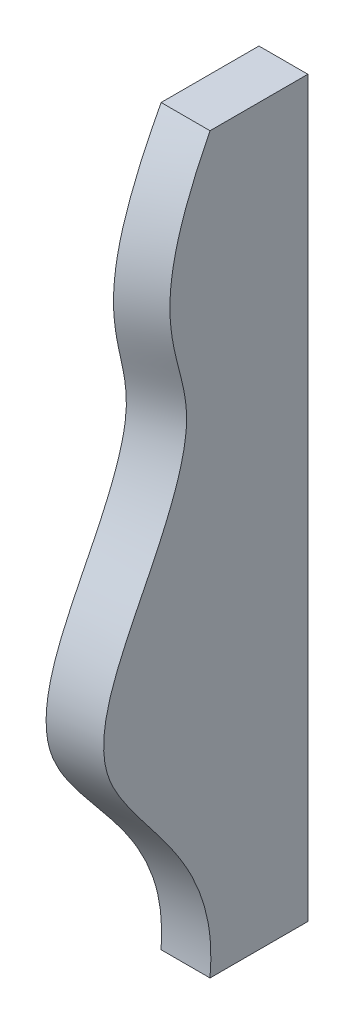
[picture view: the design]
ISO-10303-21;
HEADER;
FILE_DESCRIPTION(('STEP AP214'),'2;1');
FILE_NAME('part.step','',(''),(''),'','','');
FILE_SCHEMA(('AUTOMOTIVE_DESIGN { 1 0 10303 214 1 1 1 1 }'));
ENDSEC;
DATA;
#1=APPLICATION_CONTEXT('core data for automotive mechanical design processes');
#2=APPLICATION_PROTOCOL_DEFINITION('international standard','automotive_design',2000,#1);
#3=PRODUCT_CONTEXT('',#1,'mechanical');
#4=PRODUCT('Part','Part','',(#3));
#5=PRODUCT_RELATED_PRODUCT_CATEGORY('part','',(#4));
#6=PRODUCT_DEFINITION_FORMATION('','',#4);
#7=PRODUCT_DEFINITION_CONTEXT('part definition',#1,'design');
#8=PRODUCT_DEFINITION('design','',#6,#7);
#9=PRODUCT_DEFINITION_SHAPE('','',#8);
#10=(LENGTH_UNIT() NAMED_UNIT(*) SI_UNIT(.MILLI.,.METRE.));
#11=(NAMED_UNIT(*) PLANE_ANGLE_UNIT() SI_UNIT($,.RADIAN.));
#12=(NAMED_UNIT(*) SI_UNIT($,.STERADIAN.) SOLID_ANGLE_UNIT());
#13=UNCERTAINTY_MEASURE_WITH_UNIT(LENGTH_MEASURE(1.E-05),#10,'distance_accuracy_value','');
#14=(GEOMETRIC_REPRESENTATION_CONTEXT(3) GLOBAL_UNCERTAINTY_ASSIGNED_CONTEXT((#13)) GLOBAL_UNIT_ASSIGNED_CONTEXT((#10,
#11,#12)) REPRESENTATION_CONTEXT('',''));
#15=CARTESIAN_POINT('',(0.,0.,0.));
#16=DIRECTION('',(0.,0.,1.));
#17=DIRECTION('',(1.,0.,0.));
#18=AXIS2_PLACEMENT_3D('',#15,#16,#17);
#19=CARTESIAN_POINT('',(250.,375.,253.120113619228));
#20=DIRECTION('',(1.,0.,0.));
#21=DIRECTION('',(0.,0.,-1.));
#22=AXIS2_PLACEMENT_3D('',#19,#20,#21);
#23=PLANE('',#22);
#24=CARTESIAN_POINT('',(250.,375.,100.));
#25=CARTESIAN_POINT('',(250.,373.220474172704,100.903911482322));
#26=CARTESIAN_POINT('',(250.,371.437127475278,101.800322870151));
#27=CARTESIAN_POINT('',(250.,367.861516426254,103.577630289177));
#28=CARTESIAN_POINT('',(250.,366.0692477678,104.458517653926));
#29=CARTESIAN_POINT('',(250.,362.475751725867,106.203616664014));
#30=CARTESIAN_POINT('',(250.,360.674521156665,107.06782175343));
#31=CARTESIAN_POINT('',(250.,357.063025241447,108.778305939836));
#32=CARTESIAN_POINT('',(250.,355.252757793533,109.624580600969));
#33=CARTESIAN_POINT('',(250.,351.623076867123,111.297884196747));
#34=CARTESIAN_POINT('',(250.,349.803662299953,112.12491077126));
#35=CARTESIAN_POINT('',(250.,346.155536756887,113.758313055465));
#36=CARTESIAN_POINT('',(250.,344.326825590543,114.564688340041));
#37=CARTESIAN_POINT('',(250.,340.593071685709,116.184285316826));
#38=CARTESIAN_POINT('',(250.,338.687673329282,116.996687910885));
#39=CARTESIAN_POINT('',(250.,334.866369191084,118.595935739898));
#40=CARTESIAN_POINT('',(250.,332.950464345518,119.382783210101));
#41=CARTESIAN_POINT('',(250.,329.107807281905,120.929005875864));
#42=CARTESIAN_POINT('',(250.,327.181056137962,121.688383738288));
#43=CARTESIAN_POINT('',(250.,323.316308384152,123.177600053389));
#44=CARTESIAN_POINT('',(250.,321.378312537,123.907440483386));
#45=CARTESIAN_POINT('',(250.,317.490611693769,125.335345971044));
#46=CARTESIAN_POINT('',(250.,315.540906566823,126.033410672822));
#47=CARTESIAN_POINT('',(250.,311.629251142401,127.395341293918));
#48=CARTESIAN_POINT('',(250.,309.667299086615,128.059202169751));
#49=CARTESIAN_POINT('',(250.,305.721169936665,129.353164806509));
#50=CARTESIAN_POINT('',(250.,303.736930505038,129.983076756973));
#51=CARTESIAN_POINT('',(250.,299.75582656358,131.202490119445));
#52=CARTESIAN_POINT('',(250.,297.758960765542,131.791987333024));
#53=CARTESIAN_POINT('',(250.,293.752808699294,132.927203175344));
#54=CARTESIAN_POINT('',(250.,291.743522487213,133.47292200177));
#55=CARTESIAN_POINT('',(250.,287.71268752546,134.517031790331));
#56=CARTESIAN_POINT('',(250.,285.691138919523,135.015423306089));
#57=CARTESIAN_POINT('',(250.,281.635891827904,135.961150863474));
#58=CARTESIAN_POINT('',(250.,279.602192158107,136.408481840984));
#59=CARTESIAN_POINT('',(250.,275.522710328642,137.248195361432));
#60=CARTESIAN_POINT('',(250.,273.476924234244,137.6405588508));
#61=CARTESIAN_POINT('',(250.,269.416504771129,138.358665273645));
#62=CARTESIAN_POINT('',(250.,267.40208275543,138.685599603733));
#63=CARTESIAN_POINT('',(250.,263.363817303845,139.278764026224));
#64=CARTESIAN_POINT('',(250.,261.339971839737,139.544980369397));
#65=CARTESIAN_POINT('',(250.,257.285051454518,140.012783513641));
#66=CARTESIAN_POINT('',(250.,255.253977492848,140.214378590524));
#67=CARTESIAN_POINT('',(250.,251.186828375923,140.549420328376));
#68=CARTESIAN_POINT('',(250.,249.150755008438,140.682888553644));
#69=CARTESIAN_POINT('',(250.,245.075897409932,140.878750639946));
#70=CARTESIAN_POINT('',(250.,243.037114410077,140.941169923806));
#71=CARTESIAN_POINT('',(250.,238.959181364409,140.992821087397));
#72=CARTESIAN_POINT('',(250.,236.92003159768,140.982074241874));
#73=CARTESIAN_POINT('',(250.,233.10922731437,140.892630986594));
#74=CARTESIAN_POINT('',(250.,231.337355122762,140.822975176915));
#75=CARTESIAN_POINT('',(250.,227.796421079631,140.627732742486));
#76=CARTESIAN_POINT('',(250.,226.027359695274,140.502137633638));
#77=CARTESIAN_POINT('',(250.,222.493734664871,140.196136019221));
#78=CARTESIAN_POINT('',(250.,220.729171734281,140.015721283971));
#79=CARTESIAN_POINT('',(250.,217.206088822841,139.602317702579));
#80=CARTESIAN_POINT('',(250.,215.447569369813,139.369324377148));
#81=CARTESIAN_POINT('',(250.,211.937980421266,138.85423527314));
#82=CARTESIAN_POINT('',(250.,210.186910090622,138.572145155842));
#83=CARTESIAN_POINT('',(250.,206.693470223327,137.963660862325));
#84=CARTESIAN_POINT('',(250.,204.951096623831,137.637289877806));
#85=CARTESIAN_POINT('',(250.,201.447659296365,136.940741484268));
#86=CARTESIAN_POINT('',(250.,199.686713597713,136.569974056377));
#87=CARTESIAN_POINT('',(250.,196.172554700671,135.796172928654));
#88=CARTESIAN_POINT('',(250.,194.419339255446,135.393149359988));
#89=CARTESIAN_POINT('',(250.,190.918463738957,134.563170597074));
#90=CARTESIAN_POINT('',(250.,189.170804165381,134.136213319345));
#91=CARTESIAN_POINT('',(250.,185.678601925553,133.267747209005));
#92=CARTESIAN_POINT('',(250.,183.934060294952,132.826234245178));
#93=CARTESIAN_POINT('',(250.,180.445427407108,131.938950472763));
#94=CARTESIAN_POINT('',(250.,178.701336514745,131.493178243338));
#95=CARTESIAN_POINT('',(250.,175.210752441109,130.608385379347));
#96=CARTESIAN_POINT('',(250.,173.464258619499,130.169367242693));
#97=CARTESIAN_POINT('',(250.,170.339071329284,129.401270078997));
#98=CARTESIAN_POINT('',(250.,168.961244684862,129.068686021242));
#99=CARTESIAN_POINT('',(250.,166.20164596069,128.420662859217));
#100=CARTESIAN_POINT('',(250.,164.819874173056,128.105222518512));
#101=CARTESIAN_POINT('',(250.,162.051733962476,127.497244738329));
#102=CARTESIAN_POINT('',(250.,160.665367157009,127.204699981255));
#103=CARTESIAN_POINT('',(250.,157.887431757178,126.648053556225));
#104=CARTESIAN_POINT('',(250.,156.495865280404,126.38394139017));
#105=CARTESIAN_POINT('',(250.,153.706996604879,125.889358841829));
#106=CARTESIAN_POINT('',(250.,152.309695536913,125.658882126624));
#107=CARTESIAN_POINT('',(250.,149.508914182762,125.236321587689));
#108=CARTESIAN_POINT('',(250.,148.105432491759,125.044247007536));
#109=CARTESIAN_POINT('',(250.,145.312512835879,124.705202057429));
#110=CARTESIAN_POINT('',(250.,143.923146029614,124.55764958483));
#111=CARTESIAN_POINT('',(250.,141.139536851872,124.307536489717));
#112=CARTESIAN_POINT('',(250.,139.745292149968,124.205001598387));
#113=CARTESIAN_POINT('',(250.,136.95390733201,124.047744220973));
#114=CARTESIAN_POINT('',(250.,135.556766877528,123.993027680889));
#115=CARTESIAN_POINT('',(250.,132.761607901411,123.933312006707));
#116=CARTESIAN_POINT('',(250.,131.363589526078,123.928306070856));
#117=CARTESIAN_POINT('',(250.,128.568653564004,123.969032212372));
#118=CARTESIAN_POINT('',(250.,127.171735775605,124.014749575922));
#119=CARTESIAN_POINT('',(250.,125.078670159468,124.121503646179));
#120=CARTESIAN_POINT('',(250.,124.381497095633,124.163439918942));
#121=CARTESIAN_POINT('',(250.,122.988014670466,124.259976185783));
#122=CARTESIAN_POINT('',(250.,122.291705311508,124.314576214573));
#123=CARTESIAN_POINT('',(250.,121.14390715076,124.415057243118));
#124=CARTESIAN_POINT('',(250.,120.692095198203,124.457293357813));
#125=CARTESIAN_POINT('',(250.,119.788986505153,124.546961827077));
#126=CARTESIAN_POINT('',(250.,119.337689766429,124.594394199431));
#127=CARTESIAN_POINT('',(250.,117.984614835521,124.74416466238));
#128=CARTESIAN_POINT('',(250.,117.083655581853,124.853975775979));
#129=CARTESIAN_POINT('',(250.,115.283863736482,125.092111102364));
#130=CARTESIAN_POINT('',(250.,114.385032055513,125.220442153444));
#131=CARTESIAN_POINT('',(250.,112.590006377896,125.494270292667));
#132=CARTESIAN_POINT('',(250.,111.693812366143,125.639767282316));
#133=CARTESIAN_POINT('',(250.,109.007753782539,126.10046963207));
#134=CARTESIAN_POINT('',(250.,107.221970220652,126.439676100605));
#135=CARTESIAN_POINT('',(250.,103.660474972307,127.17408997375));
#136=CARTESIAN_POINT('',(250.,101.884773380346,127.569345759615));
#137=CARTESIAN_POINT('',(250.,98.3442194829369,128.409090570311));
#138=CARTESIAN_POINT('',(250.,96.5793724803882,128.85360190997));
#139=CARTESIAN_POINT('',(250.,93.9410074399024,129.552917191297));
#140=CARTESIAN_POINT('',(250.,93.0631243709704,129.791421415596));
#141=CARTESIAN_POINT('',(250.,91.3102085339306,130.278689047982));
#142=CARTESIAN_POINT('',(250.,90.4351757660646,130.527452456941));
#143=CARTESIAN_POINT('',(250.,87.7843646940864,131.297049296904));
#144=CARTESIAN_POINT('',(250.,86.0130079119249,131.833170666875));
#145=CARTESIAN_POINT('',(250.,82.4833365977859,132.941367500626));
#146=CARTESIAN_POINT('',(250.,80.7250119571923,133.513410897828));
#147=CARTESIAN_POINT('',(250.,77.220409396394,134.690089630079));
#148=CARTESIAN_POINT('',(250.,75.4741253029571,135.29470660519));
#149=CARTESIAN_POINT('',(250.,71.9927547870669,136.533485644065));
#150=CARTESIAN_POINT('',(250.,70.2576647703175,137.167637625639));
#151=CARTESIAN_POINT('',(250.,66.797916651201,138.462705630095));
#152=CARTESIAN_POINT('',(250.,65.0732565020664,139.123616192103));
#153=CARTESIAN_POINT('',(250.,61.6336938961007,140.469640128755));
#154=CARTESIAN_POINT('',(250.,59.9187901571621,141.154750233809));
#155=CARTESIAN_POINT('',(250.,55.0678159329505,143.128814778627));
#156=CARTESIAN_POINT('',(250.,51.9422919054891,144.443723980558));
#157=CARTESIAN_POINT('',(250.,45.7169576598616,147.134178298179));
#158=CARTESIAN_POINT('',(250.,42.6171519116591,148.509733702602));
#159=CARTESIAN_POINT('',(250.,36.4384237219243,151.309960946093));
#160=CARTESIAN_POINT('',(250.,33.3595097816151,152.734651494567));
#161=CARTESIAN_POINT('',(250.,27.2181158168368,155.622266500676));
#162=CARTESIAN_POINT('',(250.,24.1556433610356,157.085207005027));
#163=CARTESIAN_POINT('',(250.,18.0428027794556,160.038725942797));
#164=CARTESIAN_POINT('',(250.,14.9924391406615,161.529313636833));
#165=CARTESIAN_POINT('',(250.,8.89945845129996,164.527453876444));
#166=CARTESIAN_POINT('',(250.,5.85684276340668,166.03500918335));
#167=CARTESIAN_POINT('',(250.,-0.205008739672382,169.045979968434));
#168=CARTESIAN_POINT('',(250.,-3.22426451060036,170.549355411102));
#169=CARTESIAN_POINT('',(250.,-9.26474357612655,173.550525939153));
#170=CARTESIAN_POINT('',(250.,-12.2859663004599,175.048322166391));
#171=CARTESIAN_POINT('',(250.,-16.8237551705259,177.281591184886));
#172=CARTESIAN_POINT('',(250.,-18.3370770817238,178.023647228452));
#173=CARTESIAN_POINT('',(250.,-21.3666825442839,179.501685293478));
#174=CARTESIAN_POINT('',(250.,-22.8829660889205,180.237667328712));
#175=CARTESIAN_POINT('',(250.,-25.9186919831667,181.701477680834));
#176=CARTESIAN_POINT('',(250.,-27.4381327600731,182.429309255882));
#177=CARTESIAN_POINT('',(250.,-30.4816464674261,183.875214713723));
#178=CARTESIAN_POINT('',(250.,-32.0057193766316,184.593288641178));
#179=CARTESIAN_POINT('',(250.,-35.0588747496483,186.017388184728));
#180=CARTESIAN_POINT('',(250.,-36.5879553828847,186.723417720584));
#181=CARTESIAN_POINT('',(250.,-39.6525274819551,188.12144879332));
#182=CARTESIAN_POINT('',(250.,-41.1880189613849,188.813450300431));
#183=CARTESIAN_POINT('',(250.,-44.2663550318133,190.181027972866));
#184=CARTESIAN_POINT('',(250.,-45.8091997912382,190.856603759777));
#185=CARTESIAN_POINT('',(250.,-48.9030941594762,192.18867137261));
#186=CARTESIAN_POINT('',(250.,-50.4541437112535,192.845163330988));
#187=CARTESIAN_POINT('',(250.,-54.4318586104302,194.495804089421));
#188=CARTESIAN_POINT('',(250.,-56.8650386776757,195.474355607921));
#189=CARTESIAN_POINT('',(250.,-61.7571177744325,197.366451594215));
#190=CARTESIAN_POINT('',(250.,-64.2160209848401,198.279985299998));
#191=CARTESIAN_POINT('',(250.,-69.1625625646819,200.028280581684));
#192=CARTESIAN_POINT('',(250.,-71.6502082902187,200.863021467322));
#193=CARTESIAN_POINT('',(250.,-76.6574875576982,202.438339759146));
#194=CARTESIAN_POINT('',(250.,-79.1771444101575,203.17884363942));
#195=CARTESIAN_POINT('',(250.,-84.2466743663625,204.547045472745));
#196=CARTESIAN_POINT('',(250.,-86.7965423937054,205.174762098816));
#197=CARTESIAN_POINT('',(250.,-91.9249631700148,206.297747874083));
#198=CARTESIAN_POINT('',(250.,-94.5035064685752,206.793059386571));
#199=CARTESIAN_POINT('',(250.,-98.456955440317,207.43182726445));
#200=CARTESIAN_POINT('',(250.,-99.8230174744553,207.630775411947));
#201=CARTESIAN_POINT('',(250.,-102.561089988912,207.98309634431));
#202=CARTESIAN_POINT('',(250.,-103.933100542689,208.13646856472));
#203=CARTESIAN_POINT('',(250.,-106.681629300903,208.394458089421));
#204=CARTESIAN_POINT('',(250.,-108.058147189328,208.499078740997));
#205=CARTESIAN_POINT('',(250.,-110.814293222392,208.656486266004));
#206=CARTESIAN_POINT('',(250.,-112.193921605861,208.709269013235));
#207=CARTESIAN_POINT('',(250.,-114.947533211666,208.759889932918));
#208=CARTESIAN_POINT('',(250.,-116.321511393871,208.7579931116));
#209=CARTESIAN_POINT('',(250.,-119.068376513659,208.697184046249));
#210=CARTESIAN_POINT('',(250.,-120.441263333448,208.638266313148));
#211=CARTESIAN_POINT('',(250.,-123.183168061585,208.460988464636));
#212=CARTESIAN_POINT('',(250.,-124.552186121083,208.342630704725));
#213=CARTESIAN_POINT('',(250.,-127.283633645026,208.044422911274));
#214=CARTESIAN_POINT('',(250.,-128.646062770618,207.864569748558));
#215=CARTESIAN_POINT('',(250.,-131.098417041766,207.482729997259));
#216=CARTESIAN_POINT('',(250.,-132.190067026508,207.291757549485));
#217=CARTESIAN_POINT('',(250.,-134.365422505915,206.868231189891));
#218=CARTESIAN_POINT('',(250.,-135.449127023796,206.635672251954));
#219=CARTESIAN_POINT('',(250.,-137.606641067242,206.128688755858));
#220=CARTESIAN_POINT('',(250.,-138.680451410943,205.854267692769));
#221=CARTESIAN_POINT('',(250.,-140.282297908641,205.411261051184));
#222=CARTESIAN_POINT('',(250.,-140.814722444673,205.258377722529));
#223=CARTESIAN_POINT('',(250.,-141.87646630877,204.942159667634));
#224=CARTESIAN_POINT('',(250.,-142.405785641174,204.778824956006));
#225=CARTESIAN_POINT('',(250.,-143.460924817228,204.441810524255));
#226=CARTESIAN_POINT('',(250.,-143.986745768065,204.268134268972));
#227=CARTESIAN_POINT('',(250.,-145.034842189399,203.910398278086));
#228=CARTESIAN_POINT('',(250.,-145.557117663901,203.726338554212));
#229=CARTESIAN_POINT('',(250.,-146.600060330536,203.347542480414));
#230=CARTESIAN_POINT('',(250.,-147.120713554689,203.152767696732));
#231=CARTESIAN_POINT('',(250.,-148.158376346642,202.753758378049));
#232=CARTESIAN_POINT('',(250.,-148.675385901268,202.549523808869));
#233=CARTESIAN_POINT('',(250.,-150.221089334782,201.923387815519));
#234=CARTESIAN_POINT('',(250.,-151.244377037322,201.488083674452));
#235=CARTESIAN_POINT('',(250.,-153.277299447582,200.585865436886));
#236=CARTESIAN_POINT('',(250.,-154.286929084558,200.118939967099));
#237=CARTESIAN_POINT('',(250.,-155.791633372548,199.397985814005));
#238=CARTESIAN_POINT('',(250.,-156.291649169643,199.154203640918));
#239=CARTESIAN_POINT('',(250.,-157.288497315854,198.660215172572));
#240=CARTESIAN_POINT('',(250.,-157.785329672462,198.410008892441));
#241=CARTESIAN_POINT('',(250.,-159.271046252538,197.65026461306));
#242=CARTESIAN_POINT('',(250.,-160.255247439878,197.131554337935));
#243=CARTESIAN_POINT('',(250.,-162.813041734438,195.746561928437));
#244=CARTESIAN_POINT('',(250.,-164.3770739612,194.862612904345));
#245=CARTESIAN_POINT('',(250.,-167.476450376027,193.046928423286));
#246=CARTESIAN_POINT('',(250.,-169.011801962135,192.115205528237));
#247=CARTESIAN_POINT('',(250.,-172.057758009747,190.211501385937));
#248=CARTESIAN_POINT('',(250.,-173.568356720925,189.239510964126));
#249=CARTESIAN_POINT('',(250.,-176.568196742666,187.262074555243));
#250=CARTESIAN_POINT('',(250.,-178.057430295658,186.256616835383));
#251=CARTESIAN_POINT('',(250.,-181.017530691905,184.218419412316));
#252=CARTESIAN_POINT('',(250.,-182.488393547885,183.18567393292));
#253=CARTESIAN_POINT('',(250.,-185.414396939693,181.098560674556));
#254=CARTESIAN_POINT('',(250.,-186.86953932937,180.044195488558));
#255=CARTESIAN_POINT('',(250.,-189.774608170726,177.91308548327));
#256=CARTESIAN_POINT('',(250.,-191.224471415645,176.836254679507));
#257=CARTESIAN_POINT('',(250.,-194.113922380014,174.670108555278));
#258=CARTESIAN_POINT('',(250.,-195.553513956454,173.580798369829));
#259=CARTESIAN_POINT('',(250.,-198.425481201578,171.39338261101));
#260=CARTESIAN_POINT('',(250.,-199.857858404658,170.295279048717));
#261=CARTESIAN_POINT('',(250.,-202.718235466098,168.093679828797));
#262=CARTESIAN_POINT('',(250.,-204.146235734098,166.990184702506));
#263=CARTESIAN_POINT('',(250.,-207.000518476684,164.780972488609));
#264=CARTESIAN_POINT('',(250.,-208.426800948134,163.675255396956));
#265=CARTESIAN_POINT('',(250.,-211.280155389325,161.464575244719));
#266=CARTESIAN_POINT('',(250.,-212.707227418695,160.359612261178));
#267=CARTESIAN_POINT('',(250.,-216.435546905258,157.4807288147));
#268=CARTESIAN_POINT('',(250.,-218.739129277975,155.709821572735));
#269=CARTESIAN_POINT('',(250.,-223.362851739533,152.1893141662));
#270=CARTESIAN_POINT('',(250.,-225.682993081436,150.439715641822));
#271=CARTESIAN_POINT('',(250.,-230.347568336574,146.973176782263));
#272=CARTESIAN_POINT('',(250.,-232.69200187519,145.256235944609));
#273=CARTESIAN_POINT('',(250.,-237.412529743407,141.865861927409));
#274=CARTESIAN_POINT('',(250.,-239.788626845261,140.192432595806));
#275=CARTESIAN_POINT('',(250.,-244.579566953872,136.899541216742));
#276=CARTESIAN_POINT('',(250.,-246.994426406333,135.28010302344));
#277=CARTESIAN_POINT('',(250.,-251.850823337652,132.117701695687));
#278=CARTESIAN_POINT('',(250.,-254.29207365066,130.574298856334));
#279=CARTESIAN_POINT('',(250.,-259.221670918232,127.56305965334));
#280=CARTESIAN_POINT('',(250.,-261.710028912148,126.095241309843));
#281=CARTESIAN_POINT('',(250.,-266.735426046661,123.246924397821));
#282=CARTESIAN_POINT('',(250.,-269.272450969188,121.866400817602));
#283=CARTESIAN_POINT('',(250.,-274.396246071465,119.203548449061));
#284=CARTESIAN_POINT('',(250.,-276.982994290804,117.921177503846));
#285=CARTESIAN_POINT('',(250.,-282.20686687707,115.46449800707));
#286=CARTESIAN_POINT('',(250.,-284.843980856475,114.290167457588));
#287=CARTESIAN_POINT('',(250.,-289.395767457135,112.382264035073));
#288=CARTESIAN_POINT('',(250.,-291.298284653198,111.619597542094));
#289=CARTESIAN_POINT('',(250.,-295.127382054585,110.15637406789));
#290=CARTESIAN_POINT('',(250.,-297.053965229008,109.45582483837));
#291=CARTESIAN_POINT('',(250.,-300.929560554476,108.119686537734));
#292=CARTESIAN_POINT('',(250.,-302.878572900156,107.484098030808));
#293=CARTESIAN_POINT('',(250.,-306.797266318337,106.280211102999));
#294=CARTESIAN_POINT('',(250.,-308.766947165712,105.711911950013));
#295=CARTESIAN_POINT('',(250.,-312.725043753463,104.64444030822));
#296=CARTESIAN_POINT('',(250.,-314.713460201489,104.145270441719));
#297=CARTESIAN_POINT('',(250.,-318.709389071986,103.216822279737));
#298=CARTESIAN_POINT('',(250.,-320.716923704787,102.787639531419));
#299=CARTESIAN_POINT('',(250.,-324.746132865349,102.000807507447));
#300=CARTESIAN_POINT('',(250.,-326.767808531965,101.643164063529));
#301=CARTESIAN_POINT('',(250.,-330.822481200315,100.999799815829));
#302=CARTESIAN_POINT('',(250.,-332.855477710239,100.714075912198));
#303=CARTESIAN_POINT('',(250.,-336.929880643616,100.21439874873));
#304=CARTESIAN_POINT('',(250.,-338.971285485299,100.000432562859));
#305=CARTESIAN_POINT('',(250.,-343.059585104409,99.6436103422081));
#306=CARTESIAN_POINT('',(250.,-345.106477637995,99.500728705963));
#307=CARTESIAN_POINT('',(250.,-348.316815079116,99.3316000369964));
#308=CARTESIAN_POINT('',(250.,-349.47906530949,99.2816386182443));
#309=CARTESIAN_POINT('',(250.,-351.804073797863,99.2039390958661));
#310=CARTESIAN_POINT('',(250.,-352.966831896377,99.1761962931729));
#311=CARTESIAN_POINT('',(250.,-355.292518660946,99.1426329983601));
#312=CARTESIAN_POINT('',(250.,-356.455447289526,99.1368098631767));
#313=CARTESIAN_POINT('',(250.,-358.781158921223,99.1467575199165));
#314=CARTESIAN_POINT('',(250.,-359.943941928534,99.1625273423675));
#315=CARTESIAN_POINT('',(250.,-362.266071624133,99.2152439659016));
#316=CARTESIAN_POINT('',(250.,-363.425419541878,99.252136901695));
#317=CARTESIAN_POINT('',(250.,-365.743328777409,99.3466908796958));
#318=CARTESIAN_POINT('',(250.,-366.901890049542,99.4043530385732));
#319=CARTESIAN_POINT('',(250.,-369.217906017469,99.5400597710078));
#320=CARTESIAN_POINT('',(250.,-370.375360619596,99.6181059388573));
#321=CARTESIAN_POINT('',(250.,-372.688850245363,99.7941737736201));
#322=CARTESIAN_POINT('',(250.,-373.844885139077,99.8921971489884));
#323=CARTESIAN_POINT('',(250.,-375.,100.));
#324=B_SPLINE_CURVE_WITH_KNOTS('',3,(#24,#25,#26,#27,#28,#29,#30,#31,#32,#33,#34,#35,#36,#37,
#38,#39,#40,#41,#42,#43,#44,#45,#46,#47,#48,#49,#50,#51,#52,#53,#54,#55,#56,#57,#58,#59,#60,#61,
#62,#63,#64,#65,#66,#67,#68,#69,#70,#71,#72,#73,#74,#75,#76,#77,#78,#79,#80,#81,#82,#83,#84,#85,
#86,#87,#88,#89,#90,#91,#92,#93,#94,#95,#96,#97,#98,#99,#100,#101,#102,#103,#104,#105,#106,#107,
#108,#109,#110,#111,#112,#113,#114,#115,#116,#117,#118,#119,#120,#121,#122,#123,#124,#125,#126,
#127,#128,#129,#130,#131,#132,#133,#134,#135,#136,#137,#138,#139,#140,#141,#142,#143,#144,#145,
#146,#147,#148,#149,#150,#151,#152,#153,#154,#155,#156,#157,#158,#159,#160,#161,#162,#163,#164,
#165,#166,#167,#168,#169,#170,#171,#172,#173,#174,#175,#176,#177,#178,#179,#180,#181,#182,#183,
#184,#185,#186,#187,#188,#189,#190,#191,#192,#193,#194,#195,#196,#197,#198,#199,#200,#201,#202,
#203,#204,#205,#206,#207,#208,#209,#210,#211,#212,#213,#214,#215,#216,#217,#218,#219,#220,#221,
#222,#223,#224,#225,#226,#227,#228,#229,#230,#231,#232,#233,#234,#235,#236,#237,#238,#239,#240,
#241,#242,#243,#244,#245,#246,#247,#248,#249,#250,#251,#252,#253,#254,#255,#256,#257,#258,#259,
#260,#261,#262,#263,#264,#265,#266,#267,#268,#269,#270,#271,#272,#273,#274,#275,#276,#277,#278,
#279,#280,#281,#282,#283,#284,#285,#286,#287,#288,#289,#290,#291,#292,#293,#294,#295,#296,#297,
#298,#299,#300,#301,#302,#303,#304,#305,#306,#307,#308,#309,#310,#311,#312,#313,#314,#315,#316,
#317,#318,#319,#320,#321,#322,#323),.UNSPECIFIED.,.F.,.F.,(4,2,2,2,2,2,2,2,2,2,2,2,2,2,2,2,2,2,
2,2,2,2,2,2,2,2,2,2,2,2,2,2,2,2,2,2,2,2,2,2,2,2,2,2,2,2,2,2,2,2,2,2,2,2,2,2,2,2,2,2,2,2,2,2,2,2,
2,2,2,2,2,2,2,2,2,2,2,2,2,2,2,2,2,2,2,2,2,2,2,2,2,2,2,2,2,2,2,2,2,2,2,2,2,2,2,2,2,2,2,2,2,2,2,2,
2,2,2,2,2,2,2,2,2,2,2,2,2,2,2,2,2,2,2,2,2,2,2,2,2,2,2,2,2,2,2,2,2,2,2,4),(0.,5.98781072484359,
11.9788645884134,17.9722268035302,23.9670548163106,29.9626140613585,35.9582966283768,
42.1722095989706,48.3855775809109,54.5983407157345,60.8106872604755,67.0231033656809,
73.2364329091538,79.4815074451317,85.7272297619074,91.9729238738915,98.2185449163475,
104.464784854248,110.7131846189,116.834657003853,122.957514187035,129.079586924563,
135.199720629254,141.31766373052,147.433827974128,152.75268335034,158.072345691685,
163.392807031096,168.713721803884,174.034023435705,179.351549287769,184.7498334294,
190.14642865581,195.543494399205,200.942105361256,206.342584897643,211.7450159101,
215.997136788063,220.24895058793,224.499399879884,228.748274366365,232.996347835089,
237.245442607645,241.436300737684,245.629551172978,249.823322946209,254.016520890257,
258.208502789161,260.303709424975,262.398921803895,263.760239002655,265.121560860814,
267.84421557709,270.567878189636,273.291525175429,278.743531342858,284.200272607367,
289.65949619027,292.388559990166,295.117624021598,300.669278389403,306.216045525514,
311.759718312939,317.301512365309,322.84218109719,328.382104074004,338.553795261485,
348.727218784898,358.904559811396,369.086241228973,379.271396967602,389.458234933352,
399.576758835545,409.693083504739,414.749466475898,419.80583797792,424.860110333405,
429.914359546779,434.966931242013,440.019513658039,445.072212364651,450.1248759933,
457.991824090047,465.860071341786,473.730379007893,481.606790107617,489.481895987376,
497.354479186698,501.495260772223,505.636093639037,509.7766421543,513.917520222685,
518.038332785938,522.159542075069,526.280588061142,530.40184377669,533.725761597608,
537.05008141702,540.374123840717,542.035854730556,543.697583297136,545.358758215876,
547.019931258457,548.687510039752,550.355094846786,553.690522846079,557.027156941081,
558.695953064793,560.36474525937,563.702005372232,569.09053773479,574.477660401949,
579.866017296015,585.256283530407,590.647700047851,596.038473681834,601.456404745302,
606.872181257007,612.286752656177,617.700800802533,623.114858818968,628.529405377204,
637.246191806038,645.963645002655,654.680963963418,663.399051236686,672.120940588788,
680.78439032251,689.449896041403,698.112907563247,706.772177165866,715.429679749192,
721.577771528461,727.726629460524,733.875540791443,740.024385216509,746.173462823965,
752.330866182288,758.488771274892,764.646410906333,770.802940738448,776.957251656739,
780.447039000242,783.93608808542,787.424716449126,790.913188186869,794.392803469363,
797.872605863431,801.352680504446,804.833052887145),.UNSPECIFIED.);
#325=CARTESIAN_POINT('',(250.,375.,100.));
#326=VERTEX_POINT('',#325);
#327=CARTESIAN_POINT('',(250.,-375.,100.));
#328=VERTEX_POINT('',#327);
#329=EDGE_CURVE('E88',#326,#328,#324,.T.);
#330=ORIENTED_EDGE('',*,*,#329,.T.);
#331=DIRECTION('',(0.,0.,-1.));
#332=VECTOR('',#331,1.);
#333=CARTESIAN_POINT('',(250.,-375.,253.120113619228));
#334=LINE('',#333,#332);
#335=CARTESIAN_POINT('',(250.,-375.,0.));
#336=VERTEX_POINT('',#335);
#337=EDGE_CURVE('E50',#328,#336,#334,.T.);
#338=ORIENTED_EDGE('',*,*,#337,.T.);
#339=DIRECTION('',(0.,-1.,0.));
#340=VECTOR('',#339,1.);
#341=CARTESIAN_POINT('',(250.,375.,0.));
#342=LINE('',#341,#340);
#343=CARTESIAN_POINT('',(250.,375.,0.));
#344=VERTEX_POINT('',#343);
#345=EDGE_CURVE('E87',#344,#336,#342,.T.);
#346=ORIENTED_EDGE('',*,*,#345,.F.);
#347=DIRECTION('',(0.,0.,-1.));
#348=VECTOR('',#347,1.);
#349=CARTESIAN_POINT('',(250.,375.,253.120113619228));
#350=LINE('',#349,#348);
#351=EDGE_CURVE('E65',#326,#344,#350,.T.);
#352=ORIENTED_EDGE('',*,*,#351,.F.);
#353=EDGE_LOOP('',(#330,#338,#346,#352));
#354=FACE_BOUND('',#353,.T.);
#355=ADVANCED_FACE('F35',(#354),#23,.T.);
#356=CARTESIAN_POINT('',(0.,0.,0.));
#357=DIRECTION('',(0.,0.,-1.));
#358=DIRECTION('',(-1.,0.,0.));
#359=AXIS2_PLACEMENT_3D('',#356,#357,#358);
#360=PLANE('',#359);
#361=DIRECTION('',(1.,0.,0.));
#362=VECTOR('',#361,1.);
#363=CARTESIAN_POINT('',(-750.,-375.,0.));
#364=LINE('',#363,#362);
#365=CARTESIAN_POINT('',(200.,-375.,0.));
#366=VERTEX_POINT('',#365);
#367=EDGE_CURVE('E79',#366,#336,#364,.T.);
#368=ORIENTED_EDGE('',*,*,#367,.F.);
#369=DIRECTION('',(0.,1.,0.));
#370=VECTOR('',#369,1.);
#371=CARTESIAN_POINT('',(200.,375.,0.));
#372=LINE('',#371,#370);
#373=CARTESIAN_POINT('',(200.,375.,0.));
#374=VERTEX_POINT('',#373);
#375=EDGE_CURVE('E157',#366,#374,#372,.T.);
#376=ORIENTED_EDGE('',*,*,#375,.T.);
#377=DIRECTION('',(-1.,0.,0.));
#378=VECTOR('',#377,1.);
#379=CARTESIAN_POINT('',(-750.,375.,0.));
#380=LINE('',#379,#378);
#381=EDGE_CURVE('E93',#344,#374,#380,.T.);
#382=ORIENTED_EDGE('',*,*,#381,.F.);
#383=ORIENTED_EDGE('',*,*,#345,.T.);
#384=EDGE_LOOP('',(#368,#376,#382,#383));
#385=FACE_BOUND('',#384,.T.);
#386=ADVANCED_FACE('F91',(#385),#360,.T.);
#387=CARTESIAN_POINT('',(750.,-375.,100.));
#388=CARTESIAN_POINT('',(750.,-302.078506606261,100.));
#389=CARTESIAN_POINT('',(750.,-224.483786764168,100.));
#390=CARTESIAN_POINT('',(750.,-61.5160152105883,100.));
#391=CARTESIAN_POINT('',(750.,39.4445673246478,100.));
#392=CARTESIAN_POINT('',(750.,211.849847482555,100.));
#393=CARTESIAN_POINT('',(750.,298.882075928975,100.));
#394=CARTESIAN_POINT('',(750.,375.,100.));
#395=CARTESIAN_POINT('',(669.085175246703,-375.,100.));
#396=CARTESIAN_POINT('',(669.085175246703,-302.078506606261,100.));
#397=CARTESIAN_POINT('',(669.085175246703,-234.282472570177,121.198481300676));
#398=CARTESIAN_POINT('',(669.085175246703,-62.2283080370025,120.288550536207));
#399=CARTESIAN_POINT('',(669.085175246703,68.0647781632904,82.7868169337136));
#400=CARTESIAN_POINT('',(669.085175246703,240.312514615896,73.0426687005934));
#401=CARTESIAN_POINT('',(669.085175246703,298.882075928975,100.));
#402=CARTESIAN_POINT('',(669.085175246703,375.,100.));
#403=CARTESIAN_POINT('',(500.445116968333,-375.,100.));
#404=CARTESIAN_POINT('',(517.991528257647,-284.627602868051,95.5040591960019));
#405=CARTESIAN_POINT('',(530.038001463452,-221.673003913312,150.719602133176));
#406=CARTESIAN_POINT('',(473.74510655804,-71.7416270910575,167.060530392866));
#407=CARTESIAN_POINT('',(387.213321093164,45.6135081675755,91.591323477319));
#408=CARTESIAN_POINT('',(378.694107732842,207.638743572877,66.6461848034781));
#409=CARTESIAN_POINT('',(433.17831170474,253.396603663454,122.492891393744));
#410=CARTESIAN_POINT('',(500.445116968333,375.,100.));
#411=CARTESIAN_POINT('',(285.091607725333,-375.,100.));
#412=CARTESIAN_POINT('',(309.270321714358,-264.297524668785,86.4064578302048));
#413=CARTESIAN_POINT('',(325.856840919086,-200.08226970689,164.07204721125));
#414=CARTESIAN_POINT('',(247.47112957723,-80.9425320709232,234.992870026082));
#415=CARTESIAN_POINT('',(127.240382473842,2.40271344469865,186.756001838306));
#416=CARTESIAN_POINT('',(115.567806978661,152.518027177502,151.057444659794));
#417=CARTESIAN_POINT('',(191.428893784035,202.025100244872,189.039851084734));
#418=CARTESIAN_POINT('',(285.091607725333,375.,100.));
#419=CARTESIAN_POINT('',(47.4554331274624,-375.,100.));
#420=CARTESIAN_POINT('',(51.0669239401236,-278.639867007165,99.5141662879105));
#421=CARTESIAN_POINT('',(52.9210710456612,-231.452124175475,201.325948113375));
#422=CARTESIAN_POINT('',(3.18149891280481,-90.8615864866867,272.445475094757));
#423=CARTESIAN_POINT('',(-61.0346058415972,45.7948958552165,186.157760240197));
#424=CARTESIAN_POINT('',(-59.6612105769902,205.286893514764,133.941969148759));
#425=CARTESIAN_POINT('',(-11.8049718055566,220.40073671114,189.8209162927));
#426=CARTESIAN_POINT('',(47.4554331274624,375.,100.));
#427=CARTESIAN_POINT('',(-175.903454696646,-375.,100.));
#428=CARTESIAN_POINT('',(-199.823715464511,-320.588060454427,126.731848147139));
#429=CARTESIAN_POINT('',(-216.967937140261,-300.821135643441,242.921959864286));
#430=CARTESIAN_POINT('',(-184.265304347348,-55.1410097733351,206.147478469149));
#431=CARTESIAN_POINT('',(-119.865061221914,249.096629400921,-32.5779079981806));
#432=CARTESIAN_POINT('',(-104.641938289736,431.262460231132,-94.4845569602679));
#433=CARTESIAN_POINT('',(-136.623034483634,348.137040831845,60.785640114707));
#434=CARTESIAN_POINT('',(-175.903454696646,375.,100.));
#435=CARTESIAN_POINT('',(-355.235514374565,-375.,100.));
#436=CARTESIAN_POINT('',(-319.200833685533,-282.590755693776,58.2859511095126));
#437=CARTESIAN_POINT('',(-293.075279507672,-226.888141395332,104.97090627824));
#438=CARTESIAN_POINT('',(-324.119079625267,-68.6572837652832,122.102733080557));
#439=CARTESIAN_POINT('',(-398.972481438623,73.039345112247,53.3701087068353));
#440=CARTESIAN_POINT('',(-423.398679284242,233.384819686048,47.4380317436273));
#441=CARTESIAN_POINT('',(-392.720188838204,253.575952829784,124.952096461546));
#442=CARTESIAN_POINT('',(-355.235514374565,375.,100.));
#443=CARTESIAN_POINT('',(-536.684515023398,-375.,100.));
#444=CARTESIAN_POINT('',(-494.827225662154,-277.129657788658,52.0422385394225));
#445=CARTESIAN_POINT('',(-464.573647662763,-205.017596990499,67.039018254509));
#446=CARTESIAN_POINT('',(-506.334367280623,-72.2467511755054,96.5036749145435));
#447=CARTESIAN_POINT('',(-600.216684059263,9.35641022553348,95.9941925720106));
#448=CARTESIAN_POINT('',(-628.122542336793,166.946160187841,106.349064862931));
#449=CARTESIAN_POINT('',(-587.011939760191,237.095914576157,138.331902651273));
#450=CARTESIAN_POINT('',(-536.684515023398,375.,100.));
#451=CARTESIAN_POINT('',(-644.685568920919,-375.,100.));
#452=CARTESIAN_POINT('',(-644.685568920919,-302.078506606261,100.));
#453=CARTESIAN_POINT('',(-644.685568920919,-237.237234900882,127.59081546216));
#454=CARTESIAN_POINT('',(-644.685568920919,-62.4430976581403,126.406497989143));
#455=CARTESIAN_POINT('',(-644.685568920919,76.6951111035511,77.5962366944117));
#456=CARTESIAN_POINT('',(-644.685568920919,248.895340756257,64.9137717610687));
#457=CARTESIAN_POINT('',(-644.685568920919,298.882075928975,100.));
#458=CARTESIAN_POINT('',(-644.685568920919,375.,100.));
#459=CARTESIAN_POINT('',(-750.,-375.,100.));
#460=CARTESIAN_POINT('',(-750.,-302.078506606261,100.));
#461=CARTESIAN_POINT('',(-750.,-224.483786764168,100.));
#462=CARTESIAN_POINT('',(-750.,-61.5160152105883,100.));
#463=CARTESIAN_POINT('',(-750.,39.4445673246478,100.));
#464=CARTESIAN_POINT('',(-750.,211.849847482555,100.));
#465=CARTESIAN_POINT('',(-750.,298.882075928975,100.));
#466=CARTESIAN_POINT('',(-750.,375.,100.));
#467=B_SPLINE_SURFACE_WITH_KNOTS('',3,3,((#387,#388,#389,#390,#391,#392,#393,#394),(#395,#396,
#397,#398,#399,#400,#401,#402),(#403,#404,#405,#406,#407,#408,#409,#410),(#411,#412,#413,#414,
#415,#416,#417,#418),(#419,#420,#421,#422,#423,#424,#425,#426),(#427,#428,#429,#430,#431,#432,
#433,#434),(#435,#436,#437,#438,#439,#440,#441,#442),(#443,#444,#445,#446,#447,#448,#449,#450),
(#451,#452,#453,#454,#455,#456,#457,#458),(#459,#460,#461,#462,#463,#464,#465,#466)),
.UNSPECIFIED.,.F.,.F.,.F.,(4,1,1,1,1,1,1,4),(4,1,1,1,1,4),(0.,0.161829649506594,
0.33728011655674,0.430707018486,0.637101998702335,0.783997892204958,0.789371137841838,1.),(0.,
0.291685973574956,0.310378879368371,0.65187108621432,0.695528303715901,1.),.UNSPECIFIED.);
#468=CARTESIAN_POINT('',(200.,-375.,100.));
#469=CARTESIAN_POINT('',(200.,-373.382196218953,99.8707973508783));
#470=CARTESIAN_POINT('',(200.,-371.762702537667,99.7623279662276));
#471=CARTESIAN_POINT('',(200.,-368.520537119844,99.588040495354));
#472=CARTESIAN_POINT('',(200.,-366.897864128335,99.5222458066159));
#473=CARTESIAN_POINT('',(200.,-363.650791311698,99.4346225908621));
#474=CARTESIAN_POINT('',(200.,-362.026391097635,99.4128083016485));
#475=CARTESIAN_POINT('',(200.,-358.777342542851,99.4142925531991));
#476=CARTESIAN_POINT('',(200.,-357.15269420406,99.4375983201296));
#477=CARTESIAN_POINT('',(200.,-353.904621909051,99.5303155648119));
#478=CARTESIAN_POINT('',(200.,-352.281198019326,99.599729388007));
#479=CARTESIAN_POINT('',(200.,-349.037048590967,99.7854794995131));
#480=CARTESIAN_POINT('',(200.,-347.416323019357,99.9018152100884));
#481=CARTESIAN_POINT('',(200.,-344.197237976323,100.180461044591));
#482=CARTESIAN_POINT('',(200.,-342.598832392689,100.342237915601));
#483=CARTESIAN_POINT('',(200.,-339.407677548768,100.712668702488));
#484=CARTESIAN_POINT('',(200.,-337.814927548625,100.921316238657));
#485=CARTESIAN_POINT('',(200.,-334.636520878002,101.385670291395));
#486=CARTESIAN_POINT('',(200.,-333.050863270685,101.641370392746));
#487=CARTESIAN_POINT('',(200.,-329.888039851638,102.199790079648));
#488=CARTESIAN_POINT('',(200.,-328.310873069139,102.502504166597));
#489=CARTESIAN_POINT('',(200.,-325.166385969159,103.154684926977));
#490=CARTESIAN_POINT('',(200.,-323.59906475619,103.504147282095));
#491=CARTESIAN_POINT('',(200.,-320.475595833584,104.249315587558));
#492=CARTESIAN_POINT('',(200.,-318.919447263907,104.645017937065));
#493=CARTESIAN_POINT('',(200.,-315.536571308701,105.558339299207));
#494=CARTESIAN_POINT('',(200.,-313.712286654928,106.085029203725));
#495=CARTESIAN_POINT('',(200.,-310.082643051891,107.200536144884));
#496=CARTESIAN_POINT('',(200.,-308.277285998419,107.789359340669));
#497=CARTESIAN_POINT('',(200.,-304.687094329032,109.027141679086));
#498=CARTESIAN_POINT('',(200.,-302.902262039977,109.676107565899));
#499=CARTESIAN_POINT('',(200.,-299.354587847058,111.031767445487));
#500=CARTESIAN_POINT('',(200.,-297.591746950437,111.738464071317));
#501=CARTESIAN_POINT('',(200.,-294.089371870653,113.20677887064));
#502=CARTESIAN_POINT('',(200.,-292.349834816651,113.968390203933));
#503=CARTESIAN_POINT('',(200.,-288.891471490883,115.545066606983));
#504=CARTESIAN_POINT('',(200.,-287.172687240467,116.360223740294));
#505=CARTESIAN_POINT('',(200.,-283.759505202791,118.039544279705));
#506=CARTESIAN_POINT('',(200.,-282.065104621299,118.903702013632));
#507=CARTESIAN_POINT('',(200.,-278.700461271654,120.677851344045));
#508=CARTESIAN_POINT('',(200.,-277.03021897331,121.587843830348));
#509=CARTESIAN_POINT('',(200.,-273.713563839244,123.450318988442));
#510=CARTESIAN_POINT('',(200.,-272.067151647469,124.402802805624));
#511=CARTESIAN_POINT('',(200.,-268.79775359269,126.346745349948));
#512=CARTESIAN_POINT('',(200.,-267.174765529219,127.338200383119));
#513=CARTESIAN_POINT('',(200.,-263.304731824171,129.761579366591));
#514=CARTESIAN_POINT('',(200.,-261.068441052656,131.210691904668));
#515=CARTESIAN_POINT('',(200.,-256.636666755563,134.169642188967));
#516=CARTESIAN_POINT('',(200.,-254.441181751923,135.679477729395));
#517=CARTESIAN_POINT('',(200.,-250.086593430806,138.751076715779));
#518=CARTESIAN_POINT('',(200.,-247.927493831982,140.312845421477));
#519=CARTESIAN_POINT('',(200.,-243.641187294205,143.479331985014));
#520=CARTESIAN_POINT('',(200.,-241.513979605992,145.084048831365));
#521=CARTESIAN_POINT('',(200.,-237.284332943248,148.32919616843));
#522=CARTESIAN_POINT('',(200.,-235.18191526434,149.969654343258));
#523=CARTESIAN_POINT('',(200.,-230.997939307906,153.276390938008));
#524=CARTESIAN_POINT('',(200.,-228.916378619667,154.942666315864));
#525=CARTESIAN_POINT('',(200.,-224.767520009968,158.292800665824));
#526=CARTESIAN_POINT('',(200.,-222.700221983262,159.976659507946));
#527=CARTESIAN_POINT('',(200.,-218.573073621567,163.353454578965));
#528=CARTESIAN_POINT('',(200.,-216.513223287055,165.046390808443));
#529=CARTESIAN_POINT('',(200.,-213.011816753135,167.924443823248));
#530=CARTESIAN_POINT('',(200.,-211.570210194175,169.109499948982));
#531=CARTESIAN_POINT('',(200.,-208.684503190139,171.476517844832));
#532=CARTESIAN_POINT('',(200.,-207.240402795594,172.65847967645));
#533=CARTESIAN_POINT('',(200.,-204.346947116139,175.015985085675));
#534=CARTESIAN_POINT('',(200.,-202.897591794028,176.191528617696));
#535=CARTESIAN_POINT('',(200.,-199.99070198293,178.532673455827));
#536=CARTESIAN_POINT('',(200.,-198.533166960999,179.698274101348));
#537=CARTESIAN_POINT('',(200.,-195.606797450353,182.015768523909));
#538=CARTESIAN_POINT('',(200.,-194.137960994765,183.167659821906));
#539=CARTESIAN_POINT('',(200.,-191.185890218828,185.453473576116));
#540=CARTESIAN_POINT('',(200.,-189.702653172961,186.587392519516));
#541=CARTESIAN_POINT('',(200.,-186.718823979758,188.832338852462));
#542=CARTESIAN_POINT('',(200.,-185.218231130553,189.943365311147));
#543=CARTESIAN_POINT('',(200.,-182.196681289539,192.137027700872));
#544=CARTESIAN_POINT('',(200.,-180.675726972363,193.219667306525));
#545=CARTESIAN_POINT('',(200.,-177.61012520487,195.350589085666));
#546=CARTESIAN_POINT('',(200.,-176.065480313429,196.398874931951));
#547=CARTESIAN_POINT('',(200.,-172.948736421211,198.454604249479));
#548=CARTESIAN_POINT('',(200.,-171.376632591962,199.462040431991));
#549=CARTESIAN_POINT('',(200.,-168.762589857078,201.080931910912));
#550=CARTESIAN_POINT('',(200.,-167.729449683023,201.706606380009));
#551=CARTESIAN_POINT('',(200.,-165.649607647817,202.935182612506));
#552=CARTESIAN_POINT('',(200.,-164.602904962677,203.538082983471));
#553=CARTESIAN_POINT('',(200.,-162.495387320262,204.718449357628));
#554=CARTESIAN_POINT('',(200.,-161.434574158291,205.295918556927));
#555=CARTESIAN_POINT('',(200.,-159.832318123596,206.140966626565));
#556=CARTESIAN_POINT('',(200.,-159.296428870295,206.419105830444));
#557=CARTESIAN_POINT('',(200.,-158.220870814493,206.967977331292));
#558=CARTESIAN_POINT('',(200.,-157.681202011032,207.238709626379));
#559=CARTESIAN_POINT('',(200.,-156.056254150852,208.038968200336));
#560=CARTESIAN_POINT('',(200.,-154.965050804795,208.556547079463));
#561=CARTESIAN_POINT('',(200.,-152.771161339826,209.552732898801));
#562=CARTESIAN_POINT('',(200.,-151.668554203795,210.031512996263));
#563=CARTESIAN_POINT('',(200.,-150.001876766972,210.718859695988));
#564=CARTESIAN_POINT('',(200.,-149.444143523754,210.942855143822));
#565=CARTESIAN_POINT('',(200.,-148.324420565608,211.379934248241));
#566=CARTESIAN_POINT('',(200.,-147.762430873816,211.593017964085));
#567=CARTESIAN_POINT('',(200.,-146.070264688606,212.215024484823));
#568=CARTESIAN_POINT('',(200.,-144.93371974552,212.606773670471));
#569=CARTESIAN_POINT('',(200.,-142.645942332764,213.344207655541));
#570=CARTESIAN_POINT('',(200.,-141.494711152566,213.689896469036));
#571=CARTESIAN_POINT('',(200.,-139.179534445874,214.335251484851));
#572=CARTESIAN_POINT('',(200.,-138.015590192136,214.634922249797));
#573=CARTESIAN_POINT('',(200.,-135.865449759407,215.143959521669));
#574=CARTESIAN_POINT('',(200.,-134.880849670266,215.360095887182));
#575=CARTESIAN_POINT('',(200.,-132.905190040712,215.760580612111));
#576=CARTESIAN_POINT('',(200.,-131.914130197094,215.944927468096));
#577=CARTESIAN_POINT('',(200.,-128.932256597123,216.451018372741));
#578=CARTESIAN_POINT('',(200.,-126.933268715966,216.72569035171));
#579=CARTESIAN_POINT('',(200.,-122.922544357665,217.154141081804));
#580=CARTESIAN_POINT('',(200.,-120.910807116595,217.307912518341));
#581=CARTESIAN_POINT('',(200.,-116.871972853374,217.501131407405));
#582=CARTESIAN_POINT('',(200.,-114.844849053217,217.540010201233));
#583=CARTESIAN_POINT('',(200.,-110.791926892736,217.508883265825));
#584=CARTESIAN_POINT('',(200.,-108.766128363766,217.438896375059));
#585=CARTESIAN_POINT('',(200.,-104.720699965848,217.1976884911));
#586=CARTESIAN_POINT('',(200.,-102.701070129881,217.026466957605));
#587=CARTESIAN_POINT('',(200.,-98.341726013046,216.554907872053));
#588=CARTESIAN_POINT('',(200.,-96.0038096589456,216.238006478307));
#589=CARTESIAN_POINT('',(200.,-91.3460417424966,215.490035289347));
#590=CARTESIAN_POINT('',(200.,-89.0261941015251,215.058941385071));
#591=CARTESIAN_POINT('',(200.,-84.4064841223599,214.094405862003));
#592=CARTESIAN_POINT('',(200.,-82.106635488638,213.560899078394));
#593=CARTESIAN_POINT('',(200.,-77.5301425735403,212.403276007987));
#594=CARTESIAN_POINT('',(200.,-75.2534970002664,211.779164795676));
#595=CARTESIAN_POINT('',(200.,-70.7209543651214,210.450423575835));
#596=CARTESIAN_POINT('',(200.,-68.4650857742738,209.745696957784));
#597=CARTESIAN_POINT('',(200.,-63.9763757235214,208.266572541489));
#598=CARTESIAN_POINT('',(200.,-61.7435346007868,207.492173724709));
#599=CARTESIAN_POINT('',(200.,-57.3008868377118,205.883639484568));
#600=CARTESIAN_POINT('',(200.,-55.0910687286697,205.049535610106));
#601=CARTESIAN_POINT('',(200.,-50.6915858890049,203.329980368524));
#602=CARTESIAN_POINT('',(200.,-48.5019210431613,202.44452929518));
#603=CARTESIAN_POINT('',(200.,-44.2591663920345,200.679585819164));
#604=CARTESIAN_POINT('',(200.,-42.2051204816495,199.802383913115));
#605=CARTESIAN_POINT('',(200.,-38.1112701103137,198.015449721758));
#606=CARTESIAN_POINT('',(200.,-36.0714655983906,197.105717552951));
#607=CARTESIAN_POINT('',(200.,-32.0039811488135,195.259408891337));
#608=CARTESIAN_POINT('',(200.,-29.9763016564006,194.322831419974));
#609=CARTESIAN_POINT('',(200.,-25.9310552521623,192.428129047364));
#610=CARTESIAN_POINT('',(200.,-23.9134883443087,191.470004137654));
#611=CARTESIAN_POINT('',(200.,-19.8851234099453,189.536466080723));
#612=CARTESIAN_POINT('',(200.,-17.8743303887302,188.561042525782));
#613=CARTESIAN_POINT('',(200.,-13.8587148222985,186.598006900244));
#614=CARTESIAN_POINT('',(200.,-11.8538922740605,185.610394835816));
#615=CARTESIAN_POINT('',(200.,-7.84672526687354,183.626468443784));
#616=CARTESIAN_POINT('',(200.,-5.8443837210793,182.630148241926));
#617=CARTESIAN_POINT('',(200.,-1.84170247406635,180.633502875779));
#618=CARTESIAN_POINT('',(200.,0.158637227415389,179.633177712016));
#619=CARTESIAN_POINT('',(200.,4.16051284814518,177.631650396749));
#620=CARTESIAN_POINT('',(200.,6.16204869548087,176.630448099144));
#621=CARTESIAN_POINT('',(200.,10.1668237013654,174.631466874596));
#622=CARTESIAN_POINT('',(200.,12.1700628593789,173.633687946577));
#623=CARTESIAN_POINT('',(200.,18.1956203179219,170.645535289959));
#624=CARTESIAN_POINT('',(200.,22.2232041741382,168.665681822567));
#625=CARTESIAN_POINT('',(200.,28.2845288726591,165.738427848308));
#626=CARTESIAN_POINT('',(200.,30.3080432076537,164.76988164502));
#627=CARTESIAN_POINT('',(200.,34.3634416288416,162.850490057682));
#628=CARTESIAN_POINT('',(200.,36.3953256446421,161.899644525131));
#629=CARTESIAN_POINT('',(200.,40.4673638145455,160.02013492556));
#630=CARTESIAN_POINT('',(200.,42.5075100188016,159.091453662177));
#631=CARTESIAN_POINT('',(200.,46.599145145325,157.259395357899));
#632=CARTESIAN_POINT('',(200.,48.6506340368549,156.356018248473));
#633=CARTESIAN_POINT('',(200.,52.7644988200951,154.579532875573));
#634=CARTESIAN_POINT('',(200.,54.8268631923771,153.706397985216));
#635=CARTESIAN_POINT('',(200.,58.9656669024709,151.994011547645));
#636=CARTESIAN_POINT('',(200.,61.04210640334,151.154760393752));
#637=CARTESIAN_POINT('',(200.,65.2097416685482,149.51525594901));
#638=CARTESIAN_POINT('',(200.,67.3009334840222,148.714992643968));
#639=CARTESIAN_POINT('',(200.,71.499639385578,147.158660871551));
#640=CARTESIAN_POINT('',(200.,73.6071528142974,146.40259063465));
#641=CARTESIAN_POINT('',(200.,77.7430040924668,144.973957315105));
#642=CARTESIAN_POINT('',(200.,79.7705660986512,144.299157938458));
#643=CARTESIAN_POINT('',(200.,82.8244954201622,143.325541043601));
#644=CARTESIAN_POINT('',(200.,83.8447220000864,143.007388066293));
#645=CARTESIAN_POINT('',(200.,85.889351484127,142.384758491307));
#646=CARTESIAN_POINT('',(200.,86.9137543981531,142.080281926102));
#647=CARTESIAN_POINT('',(200.,88.96714123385,141.485862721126));
#648=CARTESIAN_POINT('',(200.,89.9961265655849,141.19592494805));
#649=CARTESIAN_POINT('',(200.,92.0584067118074,140.631809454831));
#650=CARTESIAN_POINT('',(200.,93.0917014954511,140.357631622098));
#651=CARTESIAN_POINT('',(200.,95.1633946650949,139.826071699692));
#652=CARTESIAN_POINT('',(200.,96.2017961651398,139.568701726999));
#653=CARTESIAN_POINT('',(200.,98.282990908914,139.072349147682));
#654=CARTESIAN_POINT('',(200.,99.3257841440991,138.833366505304));
#655=CARTESIAN_POINT('',(200.,101.400765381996,138.378615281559));
#656=CARTESIAN_POINT('',(200.,102.432891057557,138.162562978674));
#657=CARTESIAN_POINT('',(200.,104.501334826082,137.751482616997));
#658=CARTESIAN_POINT('',(200.,105.537652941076,137.556454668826));
#659=CARTESIAN_POINT('',(200.,107.61415859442,137.189328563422));
#660=CARTESIAN_POINT('',(200.,108.654345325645,137.017225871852));
#661=CARTESIAN_POINT('',(200.,110.217479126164,136.777830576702));
#662=CARTESIAN_POINT('',(200.,110.739001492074,136.701158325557));
#663=CARTESIAN_POINT('',(200.,111.782970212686,136.554360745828));
#664=CARTESIAN_POINT('',(200.,112.30541656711,136.484235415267));
#665=CARTESIAN_POINT('',(200.,113.350588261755,136.350907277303));
#666=CARTESIAN_POINT('',(200.,113.873312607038,136.287696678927));
#667=CARTESIAN_POINT('',(200.,114.919581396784,136.168467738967));
#668=CARTESIAN_POINT('',(200.,115.443125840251,136.112449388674));
#669=CARTESIAN_POINT('',(200.,116.490950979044,136.007746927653));
#670=CARTESIAN_POINT('',(200.,117.015231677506,135.959062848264));
#671=CARTESIAN_POINT('',(200.,118.064419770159,135.869034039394));
#672=CARTESIAN_POINT('',(200.,118.58932716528,135.82768932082));
#673=CARTESIAN_POINT('',(200.,120.163530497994,135.71479059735));
#674=CARTESIAN_POINT('',(200.,121.213637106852,135.654239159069));
#675=CARTESIAN_POINT('',(200.,123.315109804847,135.562406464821));
#676=CARTESIAN_POINT('',(200.,124.366475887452,135.531125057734));
#677=CARTESIAN_POINT('',(200.,126.313605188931,135.499930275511));
#678=CARTESIAN_POINT('',(200.,127.209307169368,135.49605093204));
#679=CARTESIAN_POINT('',(200.,129.000552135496,135.508807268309));
#680=CARTESIAN_POINT('',(200.,129.896095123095,135.525442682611));
#681=CARTESIAN_POINT('',(200.,131.687273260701,135.578671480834));
#682=CARTESIAN_POINT('',(200.,132.582907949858,135.615280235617));
#683=CARTESIAN_POINT('',(200.,134.373202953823,135.707728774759));
#684=CARTESIAN_POINT('',(200.,135.267863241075,135.763569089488));
#685=CARTESIAN_POINT('',(200.,137.056977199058,135.893676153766));
#686=CARTESIAN_POINT('',(200.,137.951429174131,135.967966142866));
#687=CARTESIAN_POINT('',(200.,139.738730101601,136.133898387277));
#688=CARTESIAN_POINT('',(200.,140.631579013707,136.225541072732));
#689=CARTESIAN_POINT('',(200.,143.309768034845,136.525058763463));
#690=CARTESIAN_POINT('',(200.,145.092409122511,136.757347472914));
#691=CARTESIAN_POINT('',(200.,148.651117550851,137.276616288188));
#692=CARTESIAN_POINT('',(200.,150.427177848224,137.563643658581));
#693=CARTESIAN_POINT('',(200.,153.971396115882,138.180351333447));
#694=CARTESIAN_POINT('',(200.,155.739555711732,138.510022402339));
#695=CARTESIAN_POINT('',(200.,159.297558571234,139.205040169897));
#696=CARTESIAN_POINT('',(200.,161.087307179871,139.570865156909));
#697=CARTESIAN_POINT('',(200.,164.660820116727,140.320161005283));
#698=CARTESIAN_POINT('',(200.,166.444589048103,140.703610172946));
#699=CARTESIAN_POINT('',(200.,170.009486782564,141.475497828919));
#700=CARTESIAN_POINT('',(200.,171.790616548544,141.863931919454));
#701=CARTESIAN_POINT('',(200.,175.353420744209,142.633872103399));
#702=CARTESIAN_POINT('',(200.,177.135094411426,143.015381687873));
#703=CARTESIAN_POINT('',(200.,180.701950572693,143.760566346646));
#704=CARTESIAN_POINT('',(200.,182.487132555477,144.124243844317));
#705=CARTESIAN_POINT('',(200.,186.063707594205,144.824063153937));
#706=CARTESIAN_POINT('',(200.,187.855102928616,145.160193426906));
#707=CARTESIAN_POINT('',(200.,191.440856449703,145.795531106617));
#708=CARTESIAN_POINT('',(200.,193.235201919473,146.094809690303));
#709=CARTESIAN_POINT('',(200.,196.831876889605,146.650287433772));
#710=CARTESIAN_POINT('',(200.,198.634211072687,146.906456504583));
#711=CARTESIAN_POINT('',(200.,202.245556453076,147.369867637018));
#712=CARTESIAN_POINT('',(200.,204.054568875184,147.577100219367));
#713=CARTESIAN_POINT('',(200.,207.677799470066,147.93841458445));
#714=CARTESIAN_POINT('',(200.,209.492017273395,148.092500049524));
#715=CARTESIAN_POINT('',(200.,213.124039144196,148.344803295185));
#716=CARTESIAN_POINT('',(200.,214.94184254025,148.443030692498));
#717=CARTESIAN_POINT('',(200.,218.579289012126,148.582240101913));
#718=CARTESIAN_POINT('',(200.,220.398931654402,148.623233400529));
#719=CARTESIAN_POINT('',(200.,224.027303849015,148.647672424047));
#720=CARTESIAN_POINT('',(200.,225.83603103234,148.631473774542));
#721=CARTESIAN_POINT('',(200.,229.452402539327,148.542978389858));
#722=CARTESIAN_POINT('',(200.,231.260046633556,148.470672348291));
#723=CARTESIAN_POINT('',(200.,234.872693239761,148.271326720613));
#724=CARTESIAN_POINT('',(200.,236.677695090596,148.144275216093));
#725=CARTESIAN_POINT('',(200.,240.283547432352,147.837346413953));
#726=CARTESIAN_POINT('',(200.,242.08439701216,147.657458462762));
#727=CARTESIAN_POINT('',(200.,245.68048033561,147.247161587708));
#728=CARTESIAN_POINT('',(200.,247.475713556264,147.016748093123));
#729=CARTESIAN_POINT('',(200.,251.059095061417,146.507994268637));
#730=CARTESIAN_POINT('',(200.,252.847244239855,146.229660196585));
#731=CARTESIAN_POINT('',(200.,257.37552873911,145.465822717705));
#732=CARTESIAN_POINT('',(200.,260.110484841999,144.94940332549));
#733=CARTESIAN_POINT('',(200.,265.559938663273,143.81924037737));
#734=CARTESIAN_POINT('',(200.,268.274437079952,143.205500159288));
#735=CARTESIAN_POINT('',(200.,273.682879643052,141.889838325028));
#736=CARTESIAN_POINT('',(200.,276.3768164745,141.18788674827));
#737=CARTESIAN_POINT('',(200.,281.743790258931,139.704401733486));
#738=CARTESIAN_POINT('',(200.,284.416818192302,138.922835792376));
#739=CARTESIAN_POINT('',(200.,289.741495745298,137.288133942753));
#740=CARTESIAN_POINT('',(200.,292.393140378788,136.434981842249));
#741=CARTESIAN_POINT('',(200.,297.674404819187,134.664549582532));
#742=CARTESIAN_POINT('',(200.,300.304028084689,133.747279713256));
#743=CARTESIAN_POINT('',(200.,305.563525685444,131.847188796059));
#744=CARTESIAN_POINT('',(200.,308.193229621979,130.863897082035));
#745=CARTESIAN_POINT('',(200.,313.430922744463,128.844715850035));
#746=CARTESIAN_POINT('',(200.,316.038921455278,127.808850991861));
#747=CARTESIAN_POINT('',(200.,321.234711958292,125.68942933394));
#748=CARTESIAN_POINT('',(200.,323.8225084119,124.605883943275));
#749=CARTESIAN_POINT('',(200.,328.979167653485,122.395461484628));
#750=CARTESIAN_POINT('',(200.,331.548032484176,121.268589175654));
#751=CARTESIAN_POINT('',(200.,336.667897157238,118.97540811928));
#752=CARTESIAN_POINT('',(200.,339.218898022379,117.809101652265));
#753=CARTESIAN_POINT('',(200.,344.303946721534,115.440543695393));
#754=CARTESIAN_POINT('',(200.,346.837995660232,114.238294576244));
#755=CARTESIAN_POINT('',(200.,350.447087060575,112.497079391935));
#756=CARTESIAN_POINT('',(200.,351.528634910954,111.971550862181));
#757=CARTESIAN_POINT('',(200.,353.688833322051,110.914677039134));
#758=CARTESIAN_POINT('',(200.,354.767483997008,110.383331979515));
#759=CARTESIAN_POINT('',(200.,356.921970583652,109.315030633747));
#760=CARTESIAN_POINT('',(200.,357.997806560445,108.778074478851));
#761=CARTESIAN_POINT('',(200.,360.146744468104,107.698744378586));
#762=CARTESIAN_POINT('',(200.,361.219846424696,107.156370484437));
#763=CARTESIAN_POINT('',(200.,363.355710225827,106.070296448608));
#764=CARTESIAN_POINT('',(200.,364.418491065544,105.52663365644));
#765=CARTESIAN_POINT('',(200.,366.541503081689,104.43432328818));
#766=CARTESIAN_POINT('',(200.,367.601734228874,103.885675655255));
#767=CARTESIAN_POINT('',(200.,369.719713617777,102.783561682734));
#768=CARTESIAN_POINT('',(200.,370.777461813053,102.230095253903));
#769=CARTESIAN_POINT('',(200.,372.890538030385,101.118500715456));
#770=CARTESIAN_POINT('',(200.,373.945865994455,100.560372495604));
#771=CARTESIAN_POINT('',(200.,375.,100.));
#772=B_SPLINE_CURVE_WITH_KNOTS('',3,(#468,#469,#470,#471,#472,#473,#474,#475,#476,#477,#478,
#479,#480,#481,#482,#483,#484,#485,#486,#487,#488,#489,#490,#491,#492,#493,#494,#495,#496,#497,
#498,#499,#500,#501,#502,#503,#504,#505,#506,#507,#508,#509,#510,#511,#512,#513,#514,#515,#516,
#517,#518,#519,#520,#521,#522,#523,#524,#525,#526,#527,#528,#529,#530,#531,#532,#533,#534,#535,
#536,#537,#538,#539,#540,#541,#542,#543,#544,#545,#546,#547,#548,#549,#550,#551,#552,#553,#554,
#555,#556,#557,#558,#559,#560,#561,#562,#563,#564,#565,#566,#567,#568,#569,#570,#571,#572,#573,
#574,#575,#576,#577,#578,#579,#580,#581,#582,#583,#584,#585,#586,#587,#588,#589,#590,#591,#592,
#593,#594,#595,#596,#597,#598,#599,#600,#601,#602,#603,#604,#605,#606,#607,#608,#609,#610,#611,
#612,#613,#614,#615,#616,#617,#618,#619,#620,#621,#622,#623,#624,#625,#626,#627,#628,#629,#630,
#631,#632,#633,#634,#635,#636,#637,#638,#639,#640,#641,#642,#643,#644,#645,#646,#647,#648,#649,
#650,#651,#652,#653,#654,#655,#656,#657,#658,#659,#660,#661,#662,#663,#664,#665,#666,#667,#668,
#669,#670,#671,#672,#673,#674,#675,#676,#677,#678,#679,#680,#681,#682,#683,#684,#685,#686,#687,
#688,#689,#690,#691,#692,#693,#694,#695,#696,#697,#698,#699,#700,#701,#702,#703,#704,#705,#706,
#707,#708,#709,#710,#711,#712,#713,#714,#715,#716,#717,#718,#719,#720,#721,#722,#723,#724,#725,
#726,#727,#728,#729,#730,#731,#732,#733,#734,#735,#736,#737,#738,#739,#740,#741,#742,#743,#744,
#745,#746,#747,#748,#749,#750,#751,#752,#753,#754,#755,#756,#757,#758,#759,#760,#761,#762,#763,
#764,#765,#766,#767,#768,#769,#770,#771),.UNSPECIFIED.,.F.,.F.,(4,2,2,2,2,2,2,2,2,2,2,2,2,2,2,2,
2,2,2,2,2,2,2,2,2,2,2,2,2,2,2,2,2,2,2,2,2,2,2,2,2,2,2,2,2,2,2,2,2,2,2,2,2,2,2,2,2,2,2,2,2,2,2,2,
2,2,2,2,2,2,2,2,2,2,2,2,2,2,2,2,2,2,2,2,2,2,2,2,2,2,2,2,2,2,2,2,2,2,2,2,2,2,2,2,2,2,2,2,2,2,2,2,
2,2,2,2,2,2,2,2,2,2,2,2,2,2,2,2,2,2,2,2,2,2,2,2,2,2,2,2,2,2,2,2,2,2,2,2,2,2,2,4),(0.,
4.86878163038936,9.74023044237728,14.6132560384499,19.4870621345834,24.3611161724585,
29.2351101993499,34.054139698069,38.8725136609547,43.6902311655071,48.5073856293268,
53.3240954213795,58.1404303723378,63.8356475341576,69.5314297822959,75.2278515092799,
80.9245331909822,86.6205065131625,92.3265433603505,98.031921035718,103.737409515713,
109.443051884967,115.148154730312,123.141204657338,131.133964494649,139.127536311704,
147.120920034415,155.120732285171,163.119608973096,171.118426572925,179.117244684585,
184.715752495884,190.314148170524,195.912583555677,201.511388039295,207.11119001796,
212.712073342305,218.313183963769,223.913565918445,229.513347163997,235.114123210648,
238.737355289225,242.360808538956,245.983805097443,247.795066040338,249.606327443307,
253.228908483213,256.834312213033,258.637310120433,260.44029823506,264.045718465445,
267.650824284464,271.25557243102,274.279171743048,277.302914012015,283.351998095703,
289.401448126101,295.480790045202,301.559080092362,307.637402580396,314.712069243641,
321.78823074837,328.868909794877,335.949192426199,343.038050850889,350.127012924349,
357.21225636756,364.297459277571,370.997675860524,377.697868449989,384.39830558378,
391.098745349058,397.803363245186,404.507977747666,411.217530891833,417.927083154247,
424.641017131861,431.354949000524,444.81834624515,451.548376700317,458.278350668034,
465.002921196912,471.727473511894,478.445946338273,485.164497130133,491.881313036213,
498.597859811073,505.007896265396,508.213866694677,511.419844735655,514.626888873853,
517.833910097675,521.043218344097,524.252520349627,527.415805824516,530.579107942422,
533.741783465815,535.323134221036,536.904484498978,538.484034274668,540.063582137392,
541.643136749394,543.222693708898,546.377800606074,549.532891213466,552.21978793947,
554.906649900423,557.595582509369,560.284589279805,562.977000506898,565.669478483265,
571.061473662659,576.458145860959,581.853651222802,587.333747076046,592.80726922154,
598.276255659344,603.742403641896,609.207806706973,614.675487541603,620.132436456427,
625.593178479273,631.054977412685,636.516397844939,641.976877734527,647.436280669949,
652.861796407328,658.288212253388,663.715810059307,669.144503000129,674.573687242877,
680.002163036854,688.349922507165,696.697395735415,705.047711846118,713.401450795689,
721.757084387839,730.111380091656,738.533326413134,746.95135822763,755.367386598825,
763.782493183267,772.197113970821,780.611180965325,784.218568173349,787.825810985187,
791.432969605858,795.0400941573,798.621372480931,802.202691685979,805.784077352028,
809.365547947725),.UNSPECIFIED.);
#773=CARTESIAN_POINT('',(200.,-375.,100.));
#774=VERTEX_POINT('',#773);
#775=CARTESIAN_POINT('',(200.,375.,100.));
#776=VERTEX_POINT('',#775);
#777=EDGE_CURVE('E11',#774,#776,#772,.T.);
#778=CARTESIAN_POINT('',(-750.,-375.,100.));
#779=CARTESIAN_POINT('',(-644.685568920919,-375.,100.));
#780=CARTESIAN_POINT('',(-536.684515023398,-375.,100.));
#781=CARTESIAN_POINT('',(-355.235514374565,-375.,100.));
#782=CARTESIAN_POINT('',(-175.903454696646,-375.,100.));
#783=CARTESIAN_POINT('',(47.4554331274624,-375.,100.));
#784=CARTESIAN_POINT('',(285.091607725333,-375.,100.));
#785=CARTESIAN_POINT('',(500.445116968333,-375.,100.));
#786=CARTESIAN_POINT('',(669.085175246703,-375.,100.));
#787=CARTESIAN_POINT('',(750.,-375.,100.));
#788=B_SPLINE_CURVE_WITH_KNOTS('',3,(#778,#779,#780,#781,#782,#783,#784,#785,#786,#787),
.UNSPECIFIED.,.F.,.F.,(4,1,1,1,1,1,1,4),(0.,0.210628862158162,0.216002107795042,
0.362898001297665,0.569292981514,0.66271988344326,0.838170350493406,1.),.UNSPECIFIED.);
#789=EDGE_CURVE('E97',#774,#328,#788,.T.);
#790=CARTESIAN_POINT('',(750.,375.,100.));
#791=CARTESIAN_POINT('',(669.085175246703,375.,100.));
#792=CARTESIAN_POINT('',(500.445116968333,375.,100.));
#793=CARTESIAN_POINT('',(285.091607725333,375.,100.));
#794=CARTESIAN_POINT('',(47.4554331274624,375.,100.));
#795=CARTESIAN_POINT('',(-175.903454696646,375.,100.));
#796=CARTESIAN_POINT('',(-355.235514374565,375.,100.));
#797=CARTESIAN_POINT('',(-536.684515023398,375.,100.));
#798=CARTESIAN_POINT('',(-644.685568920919,375.,100.));
#799=CARTESIAN_POINT('',(-750.,375.,100.));
#800=B_SPLINE_CURVE_WITH_KNOTS('',3,(#790,#791,#792,#793,#794,#795,#796,#797,#798,#799),
.UNSPECIFIED.,.F.,.F.,(4,1,1,1,1,1,1,4),(0.,0.161829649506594,0.33728011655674,0.430707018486,
0.637101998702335,0.783997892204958,0.789371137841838,1.),.UNSPECIFIED.);
#801=EDGE_CURVE('E94',#326,#776,#800,.T.);
#802=ORIENTED_EDGE('',*,*,#777,.F.);
#803=ORIENTED_EDGE('',*,*,#789,.T.);
#804=ORIENTED_EDGE('',*,*,#329,.F.);
#805=ORIENTED_EDGE('',*,*,#801,.T.);
#806=EDGE_LOOP('',(#802,#803,#804,#805));
#807=FACE_BOUND('',#806,.T.);
#808=ADVANCED_FACE('F110',(#807),#467,.F.);
#809=CARTESIAN_POINT('',(-750.,375.,253.111113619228));
#810=DIRECTION('',(0.,-1.,0.));
#811=DIRECTION('',(0.,0.,-1.));
#812=AXIS2_PLACEMENT_3D('',#809,#810,#811);
#813=PLANE('',#812);
#814=DIRECTION('',(0.,0.,-1.));
#815=VECTOR('',#814,1.);
#816=CARTESIAN_POINT('',(200.,375.,253.120113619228));
#817=LINE('',#816,#815);
#818=EDGE_CURVE('E154',#776,#374,#817,.T.);
#819=ORIENTED_EDGE('',*,*,#818,.F.);
#820=ORIENTED_EDGE('',*,*,#801,.F.);
#821=ORIENTED_EDGE('',*,*,#351,.T.);
#822=ORIENTED_EDGE('',*,*,#381,.T.);
#823=EDGE_LOOP('',(#819,#820,#821,#822));
#824=FACE_BOUND('',#823,.T.);
#825=ADVANCED_FACE('F121',(#824),#813,.F.);
#826=CARTESIAN_POINT('',(-750.,-375.,253.111113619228));
#827=DIRECTION('',(0.,1.,0.));
#828=DIRECTION('',(0.,0.,1.));
#829=AXIS2_PLACEMENT_3D('',#826,#827,#828);
#830=PLANE('',#829);
#831=DIRECTION('',(0.,0.,-1.));
#832=VECTOR('',#831,1.);
#833=CARTESIAN_POINT('',(200.,-375.,253.120113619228));
#834=LINE('',#833,#832);
#835=EDGE_CURVE('E56',#774,#366,#834,.T.);
#836=ORIENTED_EDGE('',*,*,#835,.T.);
#837=ORIENTED_EDGE('',*,*,#367,.T.);
#838=ORIENTED_EDGE('',*,*,#337,.F.);
#839=ORIENTED_EDGE('',*,*,#789,.F.);
#840=EDGE_LOOP('',(#836,#837,#838,#839));
#841=FACE_BOUND('',#840,.T.);
#842=ADVANCED_FACE('F37',(#841),#830,.F.);
#843=CARTESIAN_POINT('',(200.,375.,253.120113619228));
#844=DIRECTION('',(-1.,0.,0.));
#845=DIRECTION('',(0.,-1.,0.));
#846=AXIS2_PLACEMENT_3D('',#843,#844,#845);
#847=PLANE('',#846);
#848=ORIENTED_EDGE('',*,*,#777,.T.);
#849=ORIENTED_EDGE('',*,*,#818,.T.);
#850=ORIENTED_EDGE('',*,*,#375,.F.);
#851=ORIENTED_EDGE('',*,*,#835,.F.);
#852=EDGE_LOOP('',(#848,#849,#850,#851));
#853=FACE_BOUND('',#852,.T.);
#854=ADVANCED_FACE('F145',(#853),#847,.T.);
#855=CLOSED_SHELL('',(#355,#386,#808,#825,#842,#854));
#856=MANIFOLD_SOLID_BREP('B2',#855);
#857=ADVANCED_BREP_SHAPE_REPRESENTATION('',(#18,#856),#14);
#858=SHAPE_DEFINITION_REPRESENTATION(#9,#857);
ENDSEC;
END-ISO-10303-21;
